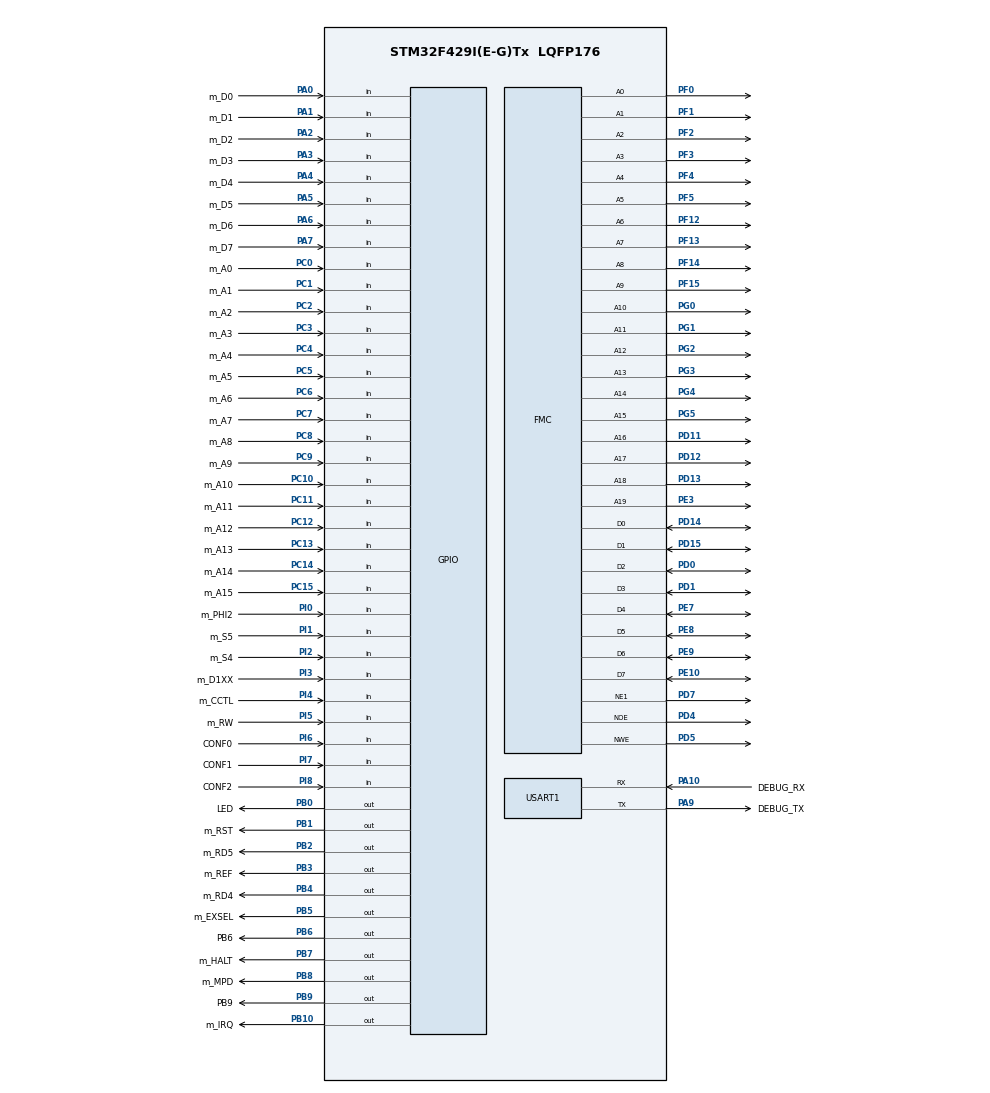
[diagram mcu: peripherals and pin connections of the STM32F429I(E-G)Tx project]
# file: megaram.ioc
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Mcu.Family=STM32F4
Mcu.Name=STM32F429I(E-G)Tx
Mcu.Package=LQFP176
NVIC.PriorityGroup=NVIC_PRIORITYGROUP_4
PA0/WKUP.GPIO_Label=m_D0
PA0/WKUP.Signal=GPIO_Input
PA1.GPIO_Label=m_D1
PA1.Signal=GPIO_Input
PA10.GPIO_Label=DEBUG_RX
PA10.Mode=Asynchronous
PA10.Signal=USART1_RX
PA2.GPIO_Label=m_D2
PA2.Signal=GPIO_Input
PA3.GPIO_Label=m_D3
PA3.Signal=GPIO_Input
PA4.GPIO_Label=m_D4
PA4.Signal=GPIO_Input
PA5.GPIO_Label=m_D5
PA5.Signal=GPIO_Input
PA6.GPIO_Label=m_D6
PA6.Signal=GPIO_Input
PA7.GPIO_Label=m_D7
PA7.Signal=GPIO_Input
PA9.GPIO_Label=DEBUG_TX
PA9.Mode=Asynchronous
PA9.Signal=USART1_TX
PB0.GPIO_Label=LED
PB0.GPIO_Speed=GPIO_SPEED_FREQ_VERY_HIGH
PB0.Signal=GPIO_Output
PB1.GPIO_Label=m_RST
PB1.GPIO_Speed=GPIO_SPEED_FREQ_VERY_HIGH
PB1.PinState=GPIO_PIN_SET
PB1.Signal=GPIO_Output
PB10.GPIO_Label=m_IRQ
PB10.GPIO_Speed=GPIO_SPEED_FREQ_VERY_HIGH
PB10.PinState=GPIO_PIN_SET
PB10.Signal=GPIO_Output
PB2/BOOT1.GPIO_Label=m_RD5
PB2/BOOT1.GPIO_Speed=GPIO_SPEED_FREQ_VERY_HIGH
PB2/BOOT1.PinState=GPIO_PIN_SET
PB2/BOOT1.Signal=GPIO_Output
PB3.GPIO_Label=m_REF
PB3.GPIO_Speed=GPIO_SPEED_FREQ_VERY_HIGH
PB3.PinState=GPIO_PIN_SET
PB3.Signal=GPIO_Output
PB4.GPIO_Label=m_RD4
PB4.GPIO_Speed=GPIO_SPEED_FREQ_VERY_HIGH
PB4.PinState=GPIO_PIN_SET
PB4.Signal=GPIO_Output
PB5.GPIO_Label=m_EXSEL
PB5.GPIO_Speed=GPIO_SPEED_FREQ_VERY_HIGH
PB5.PinState=GPIO_PIN_SET
PB5.Signal=GPIO_Output
PB6.GPIO_Label=PB6
PB6.GPIO_Speed=GPIO_SPEED_FREQ_VERY_HIGH
PB6.Signal=GPIO_Output
PB7.GPIO_Label=m_HALT
PB7.GPIO_Speed=GPIO_SPEED_FREQ_VERY_HIGH
PB7.PinState=GPIO_PIN_SET
PB7.Signal=GPIO_Output
PB8.GPIO_Label=m_MPD
PB8.GPIO_Speed=GPIO_SPEED_FREQ_VERY_HIGH
PB8.PinState=GPIO_PIN_SET
PB8.Signal=GPIO_Output
PB9.GPIO_Label=PB9
PB9.GPIO_Speed=GPIO_SPEED_FREQ_VERY_HIGH
PB9.Signal=GPIO_Output
PC0.GPIO_Label=m_A0
PC0.Signal=GPIO_Input
PC1.GPIO_Label=m_A1
PC1.Signal=GPIO_Input
PC10.GPIO_Label=m_A10
PC10.Signal=GPIO_Input
PC11.GPIO_Label=m_A11
PC11.Signal=GPIO_Input
PC12.GPIO_Label=m_A12
PC12.Signal=GPIO_Input
PC13.GPIO_Label=m_A13
PC13.Signal=GPIO_Input
PC14/OSC32_IN.GPIO_Label=m_A14
PC14/OSC32_IN.Signal=GPIO_Input
PC15/OSC32_OUT.GPIO_Label=m_A15
PC15/OSC32_OUT.Signal=GPIO_Input
PC2.GPIO_Label=m_A2
PC2.Signal=GPIO_Input
PC3.GPIO_Label=m_A3
PC3.Signal=GPIO_Input
PC4.GPIO_Label=m_A4
PC4.Signal=GPIO_Input
PC5.GPIO_Label=m_A5
PC5.Signal=GPIO_Input
PC6.GPIO_Label=m_A6
PC6.Signal=GPIO_Input
PC7.GPIO_Label=m_A7
PC7.Signal=GPIO_Input
PC8.GPIO_Label=m_A8
PC8.Signal=GPIO_Input
PC9.GPIO_Label=m_A9
PC9.Signal=GPIO_Input
PD0.Signal=FMC_D2_DA2
PD1.Signal=FMC_D3_DA3
PD11.Signal=FMC_A16_CLE
PD12.Signal=FMC_A17_ALE
PD13.Signal=FMC_A18
PD14.Signal=FMC_D0_DA0
PD15.Signal=FMC_D1_DA1
PD4.Signal=FMC_NOE
PD5.Signal=FMC_NWE
PD7.Mode=NorPsramChipSelect1_1
PD7.Signal=FMC_NE1
PE10.Signal=FMC_D7_DA7
PE3.Signal=FMC_A19
PE7.Signal=FMC_D4_DA4
PE8.Signal=FMC_D5_DA5
PE9.Signal=FMC_D6_DA6
PF0.Signal=FMC_A0
PF1.Signal=FMC_A1
PF12.Signal=FMC_A6
PF13.Signal=FMC_A7
PF14.Signal=FMC_A8
PF15.Signal=FMC_A9
PF2.Signal=FMC_A2
PF3.Signal=FMC_A3
PF4.Signal=FMC_A4
PF5.Signal=FMC_A5
PG0.Signal=FMC_A10
PG1.Signal=FMC_A11
PG2.Signal=FMC_A12
PG3.Signal=FMC_A13
PG4.Signal=FMC_A14_BA0
PG5.Signal=FMC_A15_BA1
PH0/OSC_IN.Mode=HSE-External-Clock-Source
PH0/OSC_IN.Signal=RCC_OSC_IN
PH1/OSC_OUT.Mode=HSE-External-Clock-Source
PH1/OSC_OUT.Signal=RCC_OSC_OUT
PI0.GPIO_Label=m_PHI2
PI0.Signal=GPIO_Input
PI1.GPIO_Label=m_S5
PI1.Signal=GPIO_Input
PI2.GPIO_Label=m_S4
PI2.Signal=GPIO_Input
PI3.GPIO_Label=m_D1XX
PI3.Signal=GPIO_Input
PI4.GPIO_Label=m_CCTL
PI4.Signal=GPIO_Input
PI5.GPIO_Label=m_RW
PI5.Signal=GPIO_Input
PI6.GPIO_Label=CONF0
PI6.Signal=GPIO_Input
PI7.GPIO_Label=CONF1
PI7.Signal=GPIO_Input
PI8.GPIO_Label=CONF2
PI8.Signal=GPIO_Input
ProjectManager.HeapSize=0x200
ProjectManager.StackSize=0x400
ProjectManager.TargetToolchain=Makefile
RCC.48MHZClocksFreq_Value=90000000
RCC.AHBFreq_Value=180000000
RCC.APB1CLKDivider=RCC_HCLK_DIV4
RCC.APB1Freq_Value=45000000
RCC.APB1TimFreq_Value=90000000
RCC.APB2CLKDivider=RCC_HCLK_DIV2
RCC.APB2Freq_Value=90000000
RCC.APB2TimFreq_Value=180000000
RCC.CortexFreq_Value=180000000
RCC.HCLKFreq_Value=180000000
RCC.HSE_VALUE=8000000
RCC.HSI_VALUE=16000000
RCC.LSE_VALUE=32768
RCC.PLLM=4
RCC.PLLN=180
RCC.PLLSourceVirtual=RCC_PLLSOURCE_HSE
RCC.SYSCLKFreq_VALUE=180000000
RCC.SYSCLKSource=RCC_SYSCLKSOURCE_PLLCLK
RCC.VCOOutputFreq_Value=360000000
SH.FMC_A0.0=FMC_A0,20b-a1
SH.FMC_A1.0=FMC_A1,20b-a1
SH.FMC_A10.0=FMC_A10,20b-a1
SH.FMC_A11.0=FMC_A11,20b-a1
SH.FMC_A12.0=FMC_A12,20b-a1
SH.FMC_A13.0=FMC_A13,20b-a1
SH.FMC_A14_BA0.0=FMC_A14,20b-a1
SH.FMC_A15_BA1.0=FMC_A15,20b-a1
SH.FMC_A16_CLE.0=FMC_A16,20b-a1
SH.FMC_A17_ALE.0=FMC_A17,20b-a1
SH.FMC_A18.0=FMC_A18,20b-a1
SH.FMC_A19.0=FMC_A19,20b-a1
SH.FMC_A2.0=FMC_A2,20b-a1
SH.FMC_A3.0=FMC_A3,20b-a1
SH.FMC_A4.0=FMC_A4,20b-a1
SH.FMC_A5.0=FMC_A5,20b-a1
SH.FMC_A6.0=FMC_A6,20b-a1
SH.FMC_A7.0=FMC_A7,20b-a1
SH.FMC_A8.0=FMC_A8,20b-a1
SH.FMC_A9.0=FMC_A9,20b-a1
SH.FMC_D0_DA0.0=FMC_D0,8b-d1
SH.FMC_D1_DA1.0=FMC_D1,8b-d1
SH.FMC_D2_DA2.0=FMC_D2,8b-d1
SH.FMC_D3_DA3.0=FMC_D3,8b-d1
SH.FMC_D4_DA4.0=FMC_D4,8b-d1
SH.FMC_D5_DA5.0=FMC_D5,8b-d1
SH.FMC_D6_DA6.0=FMC_D6,8b-d1
SH.FMC_D7_DA7.0=FMC_D7,8b-d1
SH.FMC_NOE.0=FMC_NOE,Sram1
SH.FMC_NWE.0=FMC_NWE,Sram1
USART1.VirtualMode=VM_ASYNC
board=custom

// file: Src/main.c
/* USER CODE BEGIN Header */
/**
  ******************************************************************************
  * @file           : main.c
  * @brief          : Main program body
  ******************************************************************************
  * @attention
  *
  * <h2><center>&copy; Copyright (c) 2019 STMicroelectronics.
  * All rights reserved.</center></h2>
  *
  * This software component is licensed by ST under BSD 3-Clause license,
  * the "License"; You may not use this file except in compliance with the
  * License. You may obtain a copy of the License at:
  *                        opensource.org/licenses/BSD-3-Clause
  *
  ******************************************************************************
  */
/* USER CODE END Header */

#include "main.h"

UART_HandleTypeDef huart1;

SRAM_HandleTypeDef hsram1;
SRAM_HandleTypeDef hsram2;

void SystemClock_Config(void);
static void MX_GPIO_Init(void);
static void MX_FSMC_Init(void);
static void MX_USART1_UART_Init(void);

int main(void)
{

  /* MCU Configuration--------------------------------------------------------*/

  /* Reset of all peripherals, Initializes the Flash interface and the Systick. */
  HAL_Init();

  /* Configure the system clock */
  SystemClock_Config();

  /* Initialize all configured peripherals */
  MX_GPIO_Init();
  MX_FSMC_Init();
  MX_USART1_UART_Init();

  /* Infinite loop */
  while (1)
  {

  }
}

void SystemClock_Config(void)
{
  RCC_OscInitTypeDef RCC_OscInitStruct = {0};
  RCC_ClkInitTypeDef RCC_ClkInitStruct = {0};

  /** Configure the main internal regulator output voltage
  */
  __HAL_RCC_PWR_CLK_ENABLE();
  __HAL_PWR_VOLTAGESCALING_CONFIG(PWR_REGULATOR_VOLTAGE_SCALE1);
  /** Initializes the CPU, AHB and APB busses clocks
  */
  RCC_OscInitStruct.OscillatorType = RCC_OSCILLATORTYPE_HSE;
  RCC_OscInitStruct.HSEState = RCC_HSE_ON;
  RCC_OscInitStruct.PLL.PLLState = RCC_PLL_ON;
  RCC_OscInitStruct.PLL.PLLSource = RCC_PLLSOURCE_HSE;
  RCC_OscInitStruct.PLL.PLLM = 4;
  RCC_OscInitStruct.PLL.PLLN = 168;
  RCC_OscInitStruct.PLL.PLLP = RCC_PLLP_DIV2;
  RCC_OscInitStruct.PLL.PLLQ = 4;
  if (HAL_RCC_OscConfig(&RCC_OscInitStruct) != HAL_OK)
  {
    Error_Handler();
  }
  /** Initializes the CPU, AHB and APB busses clocks
  */
  RCC_ClkInitStruct.ClockType = RCC_CLOCKTYPE_HCLK|RCC_CLOCKTYPE_SYSCLK
                              |RCC_CLOCKTYPE_PCLK1|RCC_CLOCKTYPE_PCLK2;
  RCC_ClkInitStruct.SYSCLKSource = RCC_SYSCLKSOURCE_PLLCLK;
  RCC_ClkInitStruct.AHBCLKDivider = RCC_SYSCLK_DIV1;
  RCC_ClkInitStruct.APB1CLKDivider = RCC_HCLK_DIV4;
  RCC_ClkInitStruct.APB2CLKDivider = RCC_HCLK_DIV2;

  if (HAL_RCC_ClockConfig(&RCC_ClkInitStruct, FLASH_LATENCY_5) != HAL_OK)
  {
    Error_Handler();
  }
}

static void MX_USART1_UART_Init(void)
{

  huart1.Instance = USART1;
  huart1.Init.BaudRate = 115200;
  huart1.Init.WordLength = UART_WORDLENGTH_8B;
  huart1.Init.StopBits = UART_STOPBITS_1;
  huart1.Init.Parity = UART_PARITY_NONE;
  huart1.Init.Mode = UART_MODE_TX_RX;
  huart1.Init.HwFlowCtl = UART_HWCONTROL_NONE;
  huart1.Init.OverSampling = UART_OVERSAMPLING_16;
  if (HAL_UART_Init(&huart1) != HAL_OK)
  {
    Error_Handler();
  }

}

static void MX_GPIO_Init(void)
{
  GPIO_InitTypeDef GPIO_InitStruct = {0};

  /* GPIO Ports Clock Enable */
  __HAL_RCC_GPIOI_CLK_ENABLE();
  __HAL_RCC_GPIOC_CLK_ENABLE();
  __HAL_RCC_GPIOF_CLK_ENABLE();
  __HAL_RCC_GPIOH_CLK_ENABLE();
  __HAL_RCC_GPIOA_CLK_ENABLE();
  __HAL_RCC_GPIOB_CLK_ENABLE();
  __HAL_RCC_GPIOG_CLK_ENABLE();
  __HAL_RCC_GPIOE_CLK_ENABLE();
  __HAL_RCC_GPIOD_CLK_ENABLE();

  /*Configure GPIO pin Output Level */
  HAL_GPIO_WritePin(GPIOB, LED_Pin|PB6_Pin|PB9_Pin, GPIO_PIN_RESET);

  /*Configure GPIO pin Output Level */
  HAL_GPIO_WritePin(GPIOB, mRST_Pin|mRD5_Pin|mIRQ_Pin|mREF_Pin
                          |mRD4_Pin|mEXSEL_Pin|mHALT_Pin|mMPD_Pin, GPIO_PIN_SET);

  /*Configure GPIO pins : mPHI2_Pin mPHI2I0_Pin mS5_Pin mS4_Pin
                           mD1XX_Pin mCCTL_Pin mRW_Pin mCONF2_Pin
                           mCONF1_Pin */
  GPIO_InitStruct.Pin = mPHI2_Pin|mPHI2I0_Pin|mS5_Pin|mS4_Pin
                          |mD1XX_Pin|mCCTL_Pin|mRW_Pin|mCONF2_Pin
                          |mCONF1_Pin;
  GPIO_InitStruct.Mode = GPIO_MODE_INPUT;
  GPIO_InitStruct.Pull = GPIO_NOPULL;
  HAL_GPIO_Init(GPIOI, &GPIO_InitStruct);

  /*Configure GPIO pins : mA13_Pin mA14_Pin mA15_Pin mA0_Pin
                           mA1_Pin mA2_Pin mA3_Pin mA4_Pin
                           mA5_Pin mA6_Pin mA7_Pin mA8_Pin
                           mA9_Pin mA10_Pin mA11_Pin mA12_Pin */
  GPIO_InitStruct.Pin = mA13_Pin|mA14_Pin|mA15_Pin|mA0_Pin
                          |mA1_Pin|mA2_Pin|mA3_Pin|mA4_Pin
                          |mA5_Pin|mA6_Pin|mA7_Pin|mA8_Pin
                          |mA9_Pin|mA10_Pin|mA11_Pin|mA12_Pin;
  GPIO_InitStruct.Mode = GPIO_MODE_INPUT;
  GPIO_InitStruct.Pull = GPIO_NOPULL;
  HAL_GPIO_Init(GPIOC, &GPIO_InitStruct);

  /*Configure GPIO pins : mD0_Pin mD1_Pin mD2_Pin mD3_Pin
                           mD4_Pin mD5_Pin mD6_Pin mD7_Pin */
  GPIO_InitStruct.Pin = mD0_Pin|mD1_Pin|mD2_Pin|mD3_Pin
                          |mD4_Pin|mD5_Pin|mD6_Pin|mD7_Pin;
  GPIO_InitStruct.Mode = GPIO_MODE_INPUT;
  GPIO_InitStruct.Pull = GPIO_NOPULL;
  HAL_GPIO_Init(GPIOA, &GPIO_InitStruct);

  /*Configure GPIO pins : LED_Pin mRST_Pin mRD5_Pin mIRQ_Pin
                           mREF_Pin mRD4_Pin mEXSEL_Pin mHALT_Pin
                           mMPD_Pin */
  GPIO_InitStruct.Pin = LED_Pin|mRST_Pin|mRD5_Pin|mIRQ_Pin
                          |mREF_Pin|mRD4_Pin|mEXSEL_Pin|mHALT_Pin
                          |mMPD_Pin;
  GPIO_InitStruct.Mode = GPIO_MODE_OUTPUT_PP;
  GPIO_InitStruct.Pull = GPIO_NOPULL;
  GPIO_InitStruct.Speed = GPIO_SPEED_FREQ_VERY_HIGH;
  HAL_GPIO_Init(GPIOB, &GPIO_InitStruct);

  /*Configure GPIO pins : PB6_Pin PB9_Pin */
  GPIO_InitStruct.Pin = PB6_Pin|PB9_Pin;
  GPIO_InitStruct.Mode = GPIO_MODE_OUTPUT_PP;
  GPIO_InitStruct.Pull = GPIO_NOPULL;
  GPIO_InitStruct.Speed = GPIO_SPEED_FREQ_LOW;
  HAL_GPIO_Init(GPIOB, &GPIO_InitStruct);

}

/* FSMC initialization function */
static void MX_FSMC_Init(void)
{

  FSMC_NORSRAM_TimingTypeDef Timing = {0};

  /** Perform the SRAM1 memory initialization sequence
  */
  hsram1.Instance = FSMC_NORSRAM_DEVICE;
  hsram1.Extended = FSMC_NORSRAM_EXTENDED_DEVICE;
  /* hsram1.Init */
  hsram1.Init.NSBank = FSMC_NORSRAM_BANK1;
  hsram1.Init.DataAddressMux = FSMC_DATA_ADDRESS_MUX_DISABLE;
  hsram1.Init.MemoryType = FSMC_MEMORY_TYPE_SRAM;
  hsram1.Init.MemoryDataWidth = FSMC_NORSRAM_MEM_BUS_WIDTH_8;
  hsram1.Init.BurstAccessMode = FSMC_BURST_ACCESS_MODE_DISABLE;
  hsram1.Init.WaitSignalPolarity = FSMC_WAIT_SIGNAL_POLARITY_LOW;
  hsram1.Init.WrapMode = FSMC_WRAP_MODE_DISABLE;
  hsram1.Init.WaitSignalActive = FSMC_WAIT_TIMING_BEFORE_WS;
  hsram1.Init.WriteOperation = FSMC_WRITE_OPERATION_DISABLE;
  hsram1.Init.WaitSignal = FSMC_WAIT_SIGNAL_DISABLE;
  hsram1.Init.ExtendedMode = FSMC_EXTENDED_MODE_DISABLE;
  hsram1.Init.AsynchronousWait = FSMC_ASYNCHRONOUS_WAIT_DISABLE;
  hsram1.Init.WriteBurst = FSMC_WRITE_BURST_DISABLE;
  hsram1.Init.PageSize = FSMC_PAGE_SIZE_NONE;
  /* Timing */
  Timing.AddressSetupTime = 15;
  Timing.AddressHoldTime = 15;
  Timing.DataSetupTime = 255;
  Timing.BusTurnAroundDuration = 15;
  Timing.CLKDivision = 16;
  Timing.DataLatency = 17;
  Timing.AccessMode = FSMC_ACCESS_MODE_A;
  /* ExtTiming */

  if (HAL_SRAM_Init(&hsram1, &Timing, NULL) != HAL_OK)
  {
    Error_Handler( );
  }

  /** Perform the SRAM2 memory initialization sequence
  */
  hsram2.Instance = FSMC_NORSRAM_DEVICE;
  hsram2.Extended = FSMC_NORSRAM_EXTENDED_DEVICE;
  /* hsram2.Init */
  hsram2.Init.NSBank = FSMC_NORSRAM_BANK2;
  hsram2.Init.DataAddressMux = FSMC_DATA_ADDRESS_MUX_DISABLE;
  hsram2.Init.MemoryType = FSMC_MEMORY_TYPE_SRAM;
  hsram2.Init.MemoryDataWidth = FSMC_NORSRAM_MEM_BUS_WIDTH_8;
  hsram2.Init.BurstAccessMode = FSMC_BURST_ACCESS_MODE_DISABLE;
  hsram2.Init.WaitSignalPolarity = FSMC_WAIT_SIGNAL_POLARITY_LOW;
  hsram2.Init.WrapMode = FSMC_WRAP_MODE_DISABLE;
  hsram2.Init.WaitSignalActive = FSMC_WAIT_TIMING_BEFORE_WS;
  hsram2.Init.WriteOperation = FSMC_WRITE_OPERATION_DISABLE;
  hsram2.Init.WaitSignal = FSMC_WAIT_SIGNAL_DISABLE;
  hsram2.Init.ExtendedMode = FSMC_EXTENDED_MODE_DISABLE;
  hsram2.Init.AsynchronousWait = FSMC_ASYNCHRONOUS_WAIT_DISABLE;
  hsram2.Init.WriteBurst = FSMC_WRITE_BURST_DISABLE;
  hsram2.Init.PageSize = FSMC_PAGE_SIZE_NONE;
  /* Timing */
  Timing.AddressSetupTime = 15;
  Timing.AddressHoldTime = 15;
  Timing.DataSetupTime = 255;
  Timing.BusTurnAroundDuration = 15;
  Timing.CLKDivision = 16;
  Timing.DataLatency = 17;
  Timing.AccessMode = FSMC_ACCESS_MODE_A;
  /* ExtTiming */

  if (HAL_SRAM_Init(&hsram2, &Timing, NULL) != HAL_OK)
  {
    Error_Handler( );
  }

}

void Error_Handler(void)
{
}

/************************ (C) COPYRIGHT STMicroelectronics *****END OF FILE****/
